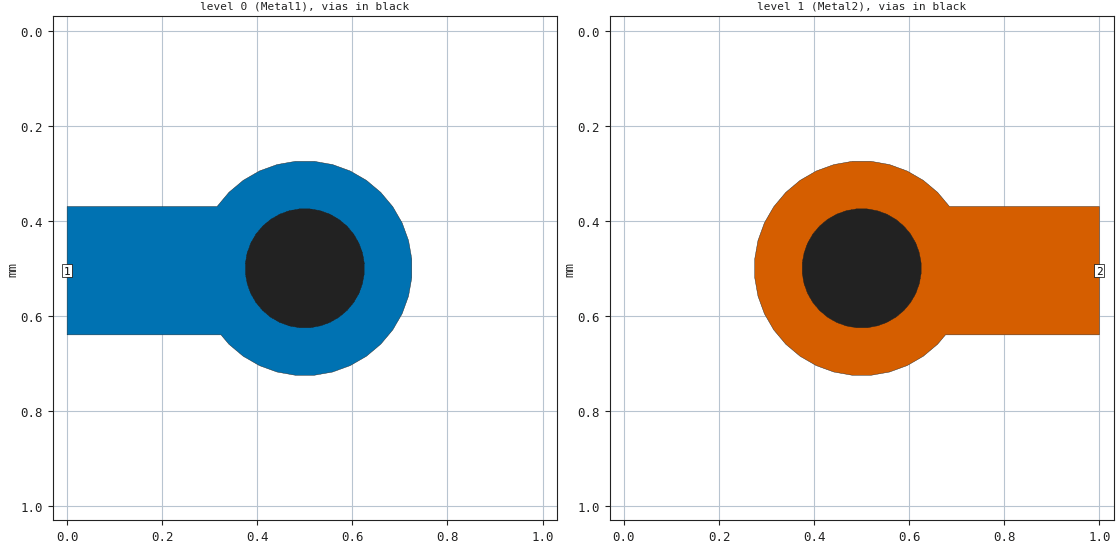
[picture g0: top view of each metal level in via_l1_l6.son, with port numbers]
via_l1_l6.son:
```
FTYP SONPROJ 17 ! Sonnet Project File
VER 17.52.2
HEADER
LIC antikernel2.1.48685 90e2ba8817c0 havequick azonenberg
DAT 07/11/2020 20:25:34
BUILT_BY_CREATED xgeom 16.56 07/03/2018 15:05:41
BUILT_BY_SAVED sonnet 17.52.2
MDATE 07/11/2020 20:25:34
HDATE 07/11/2020 20:25:34
END HEADER
DIM
ANG DEG
CAP PF
CON /OH
FREQ GHZ
IND NH
LNG MM
RES OH
END DIM
CONTROL
VARSWP
OPTIONS  -dj
SPEED 0
CACHE_ABS 1
Q_ACC N
END CONTROL
GEO
TMET "Free Space" 0 FREESPACE 376.7303136 0 0 0
BMET "Free Space" 0 FREESPACE 376.7303136 0 0 0
BRI "Alumina (96%)" 0 9.4 0.0004 0 
BRI "Alumina (99.5%)" 0 9.9 0.0001 0 
BRI "Aluminum Nitride" 0 8.6 0.0003 0 
BRI "Arlon 25FR" 0 3.58 0.0035 0 
BRI "Arlon 25N" 0 3.38 0.0025 0 
BRI "Arlon AD5" 0 5.1 0.003 0 
BRI "Arlon AD10" 0 10.2 0.005 0 
BRI "Arlon AD250" 0 2.5 0.0018 0 
BRI "Arlon AD255A" 0 2.55 0.0015 0 
BRI "Arlon AD260A" 0 2.6 0.0018 0 
BRI "Arlon AD270" 0 2.7 0.0023 0 
BRI "Arlon AD300A" 0 3 0.002 0 
BRI "Arlon AD320A" 0 3.2 0.0032 0 
BRI "Arlon AD350A" 0 3.5 0.003 0 
BRI "Arlon AD410" 0 4.1 0.003 0 
BRI "Arlon AD430" 0 4.3 0.003 0 
BRI "Arlon AD450" 0 4.5 0.0035 0 
BRI "Arlon AD600" 0 6.15 0.003 0 
BRI "Arlon AD1000" 0 10.2 0.0023 0 
BRI "Arlon AR1000" 0 9.8 0.003 0 
BRI "Arlon CLTE" 0 2.96 0.0023 0 
BRI "Arlon CLTE-AT" 0 3 0.0013 0 
BRI "Arlon CLTE-P" 0 2.94 0.0025 0 
BRI "Arlon CLTE-XT" 0 2.94 0.0012 0 
BRI "Arlon Cu 217LX" 0 2.17 0.0009 0 
BRI "Arlon Cu 233LX" 0 2.33 0.0013 0 
BRI "Arlon Cu 250GT" 0 2.5 0.001 0 
BRI "Arlon Cu 250GX" 0 2.5 0.0018 0 
BRI "Arlon Cu 6250" 0 2.32 0.0013 0 
BRI "Arlon Cu 6700" 0 2.35 0.0025 0 
BRI "Arlon Di 522" 0 2.5 0.001 0 
BRI "Arlon Di 527" 0 2.5 0.0018 0 
BRI "Arlon Di 870" 0 2.33 0.0013 0 
BRI "Arlon Di 880" 0 2.17 0.0009 0 
BRI "Arlon Iso 917" 0 2.17 0.0013 0 
BRI "Arlon Iso 933" 0 2.33 0.0016 0 
BRI "Arlon Multi HF" 0 3.7 0.004 0 
BRI "Arlon TC350" 0 3.5 0.002 0 
BRI "Arlon TC600" 0 6.15 0.002 0 
BRI "Beryllia (99.5%)" 0 6.5 0.0004 0 
BRI "CEM-1" 0 4.5 0.02 0 
BRI "CEM-3" 0 4.5 0.02 0 
BRI "Dupont 9K7" 0 7.1 0.0012 0 
BRI "Dupont 943" 0 7.4 0.002 0 
BRI "Dupont 951" 0 7.8 0.006 0 
BRI "Dupont FEP" 0 2 0.0005 0 
BRI "Dupont Vacrel" 0 3.8 0.011 0 
BRI "ESL 41010" 0 7.5 0.005 0 
BRI "ESL 41020" 0 7.25 0.005 0 
BRI "ESL 41050" 0 13.5 0.002 0 
BRI "ESL 41060" 0 16.5 0.002 0 
BRI "ESL 41110" 0 4.5 0.004 0 
BRI "Ferro A6M" 0 5.9 0.002 0 
BRI "Ferro A6S" 0 5.9 0.002 0 
BRI "Ferro L8" 0 7.3 0.0018 0 
BRI "FR-4" 0 4.4 0.02 0 
BRI "G-10" 0 4.8 0.025 0 
BRI "Gallium Arsenide" 0 12.9 0.006 0 
BRI "Gallium Nitride" 0 9.7 0 0 
BRI "Glass (Pyrex)" 0 4.82 0.0054 0 
BRI "Heraeus HL2000" 0 7.3 0.0026 0 
BRI "Isola 370HR" 0 4.04 0.021 0 
BRI "Isola FR408" 0 3.77 0.0116 0 
BRI "Isola FR408HR" 0 3.68 0.0092 0 
BRI "Isola Getek" 0 3.6 0.01 0 
BRI "Isola GI-180" 0 3.7 0.013 0 
BRI "Isola IS415" 0 3.82 0.0125 0 
BRI "Isola IS620i" 0 3.58 0.006 0 
BRI "Isola IS680-280" 0 2.8 0.0025 0 
BRI "Isola IS680-300" 0 3 0.003 0 
BRI "Isola IS680-320" 0 3.2 0.003 0 
BRI "Isola IS680-333" 0 3.33 0.003 0 
BRI "Isola IS680-338" 0 3.38 0.0032 0 
BRI "Isola IS680-345" 0 3.45 0.0036 0 
BRI "Kerafol CT800" 0 5.3 0.008 0 
BRI "Nelco MW9350" 0 3.7 0.004 0 
BRI "Nelco N4000-12" 0 3.7 0.008 0 
BRI "Nelco N4000-13" 0 3.7 0.009 0 
BRI "Nelco N4000-13SI" 0 3.2 0.007 0 
BRI "Nelco N4000-13EP" 0 3.7 0.008 0 
BRI "Nelco N4350-13RF" 0 3.5 0.0065 0 
BRI "Nelco N4380-13RF" 0 3.8 0.007 0 
BRI "Nelco N9300-13RF" 0 3 0.004 0 
BRI "Nelco N9320-13RF" 0 3.2 0.0045 0 
BRI "Nelco N9338-13RF" 0 3.38 0.0046 0 
BRI "Nelco N9350-13RF" 0 3.48 0.0055 0 
BRI "Nelco NH9294" 0 2.94 0.0022 0 
BRI "Nelco NH9300" 0 3 0.0023 0 
BRI "Nelco NH9320" 0 3.2 0.0024 0 
BRI "Nelco NH9338" 0 3.38 0.0025 0 
BRI "Nelco NH9348" 0 3.48 0.003 0 
BRI "Nelco NH9350" 0 3.5 0.003 0 
BRI "Nelco NH9410" 0 4.1 0.003 0 
BRI "Nelco NH9450" 0 4.5 0.003 0 
BRI "Nelco NX9240" 0 2.4 0.0016 0 
BRI "Nelco NX9245" 0 2.45 0.0016 0 
BRI "Nelco NX9250" 0 2.5 0.0017 0 
BRI "Nelco NX9255" 0 2.55 0.0018 0 
BRI "Nelco NX9260" 0 2.6 0.0019 0 
BRI "Nelco NY9208" 0 2.08 0.0006 0 
BRI "Nelco NY9217" 0 2.17 0.0008 0 
BRI "Nelco NY9220" 0 2.2 0.0009 0 
BRI "Nelco NY9233" 0 2.33 0.0011 0 
BRI "PET" 0 3.37 0.0208 0 
BRI "Polyimide" 0 3.5 0.003 0 
BRI "Quartz (Fused)" 0 3.78 0.0001 0 
BRI "Rogers 3001" 0 2.28 0.003 0 
BRI "Rogers RO2808" 0 7.6 0.0015 0 
BRI "Rogers RO3003" 0 3 0.0013 0 
BRI "Rogers RO3006" 0 6.5 0.002 0 
BRI "Rogers RO3010" 0 11.2 0.0022 0 
BRI "Rogers RO3035" 0 3.6 0.0018 0 
BRI "Rogers RO3203" 0 3.02 0.0016 0 
BRI "Rogers RO3206" 0 6.6 0.0027 0 
BRI "Rogers RO3210" 0 10.8 0.0027 0 
BRI "Rogers RO3730" 0 3 0.0016 0 
BRI "Rogers RO4003C" 0 3.55 0.0029 0 
BRI "Rogers RO4533" 0 3.45 0.0029 0 
BRI "Rogers RO4534" 0 3.4 0.003 0 
BRI "Rogers RO4350B" 0 3.66 0.0037 0 
BRI "Rogers RO4350BTX" 0 3.66 0.0034 0 
BRI "Rogers RO4360" 0 6.15 0.0038 0 
BRI "Rogers RO4450B-3.6" 0 3.3 0.0043 0 
BRI "Rogers RO4450B-4" 0 3.54 0.004 0 
BRI "Rogers RO4450F" 0 3.52 0.0041 0 
BRI "Rogers RO4730" 0 3 0.0033 0 
BRI "Rogers RT5870" 0 2.33 0.0012 0 
BRI "Rogers RT5880" 0 2.2 0.0009 0 
BRI "Rogers RT5880LZ" 0 1.96 0.0019 0 
BRI "Rogers RT6002" 0 2.94 0.0012 0 
BRI "Rogers RT6006" 0 6.15 0.0027 0 
BRI "Rogers RT6010LM" 0 10.9 0.0023 0 
BRI "Rogers RT6035HTC" 0 3.6 0.0013 0 
BRI "Rogers RT6202" 0 2.94 0.0015 0 
BRI "Rogers RT6202PR" 0 2.95 0.0015 0 
BRI "Rogers Syron7000" 0 3.4 0.0045 0 
BRI "Rogers Syron7100-2" 0 3.61 0.006 0 
BRI "Rogers Syron7100-4" 0 3.39 0.005 0 
BRI "Rogers Theta" 0 4.01 0.0118 0 
BRI "Rogers TMM 3" 0 3.39 0.002 0 
BRI "Rogers TMM 4" 0 4.5 0.002 0 
BRI "Rogers TMM 6" 0 6 0.0023 0 
BRI "Rogers TMM 10" 0 9.56 0.0022 0 
BRI "Rogers TMM 10i" 0 9.96 0.002 0 
BRI "Rogers UL2000" 0 2.5 0.0019 0 
BRI "Rogers UL3850" 0 3.05 0.0025 0 
BRI "Rogers UL3908" 0 2.9 0.0025 0 
BRI "Rogers XT8000" 0 3.34 0.0035 0 
BRI "Rogers XT8100-2" 0 3.54 0.0049 0 
BRI "Rogers XT8100-4" 0 3.32 0.0038 0 
BRI "Silicon (intrinsic)" 0 11.9 0.004 0.00044 
BRI "Silicon Dioxide" 0 3.9 0 0 
BRI "Silicon Nitride" 0 7.5 0 0 
BRI "Taconic CER-10" 0 10 0.0035 0 
BRI "Taconic FastFilm" 0 2.7 0.0012 0 
BRI "Taconic Fastrise-DS" 0 2.96 0.0018 0 
BRI "Taconic Fastrise27" 0 2.7 0.0014 0 
BRI "Taconic Fastrise77" 0 7.7 0.0034 0 
BRI "Taconic FEP" 0 2 0.0003 0 
BRI "Taconic RF-30" 0 3 0.0014 0 
BRI "Taconic RF-35" 0 3.5 0.0018 0 
BRI "Taconic RF-35A2" 0 3.5 0.0011 0 
BRI "Taconic RF-35P" 0 3.5 0.0025 0 
BRI "Taconic RF-41" 0 4.1 0.0038 0 
BRI "Taconic RF-43" 0 4.3 0.0033 0 
BRI "Taconic RF-45" 0 4.5 0.0037 0 
BRI "Taconic RF-60A" 0 6.15 0.0038 0 
BRI "Taconic RF-301" 0 2.97 0.0012 0 
BRI "Taconic TacBond HT" 0 2.35 0.0025 0 
BRI "Taconic TLA-6" 0 2.62 0.0012 0 
BRI "Taconic TLC-27" 0 2.75 0.003 0 
BRI "Taconic TLC-30" 0 3 0.003 0 
BRI "Taconic TLC-32" 0 3.2 0.003 0 
BRI "Taconic TLE-95" 0 2.95 0.0028 0 
BRI "Taconic TLF-34" 0 3.4 0.002 0 
BRI "Taconic TLF-35" 0 3.5 0.002 0 
BRI "Taconic TLP-3" 0 2.33 0.0009 0 
BRI "Taconic TLP-5" 0 2.2 0.0009 0 
BRI "Taconic TLP-5A" 0 2.17 0.0009 0 
BRI "Taconic TLT-0" 0 2.45 0.0006 0 
BRI "Taconic TLT-9" 0 2.5 0.0006 0 
BRI "Taconic TLT-8" 0 2.55 0.0006 0 
BRI "Taconic TLT-7" 0 2.6 0.0006 0 
BRI "Taconic TLT-6" 0 2.65 0.0006 0 
BRI "Taconic TLX-0" 0 2.45 0.0019 0 
BRI "Taconic TLX-9" 0 2.5 0.0019 0 
BRI "Taconic TLX-8" 0 2.55 0.0019 0 
BRI "Taconic TLX-7" 0 2.6 0.0019 0 
BRI "Taconic TLX-6" 0 2.65 0.0019 0 
BRI "Taconic TLY-3" 0 2.33 0.0009 0 
BRI "Taconic TLY-3F" 0 2.33 0.0009 0 
BRI "Taconic TLY-5" 0 2.2 0.0009 0 
BRI "Taconic TLY-5-L" 0 2.2 0.0009 0 
BRI "Taconic TLY-5A" 0 2.17 0.0009 0 
BRI "Taconic TLY-5A-L" 0 2.17 0.0009 0 
BRI "Taconic TPG-30" 0 3 0.0038 0 
BRI "Taconic TPG-32" 0 3.2 0.005 0 
BRI "Taconic TPG-35" 0 3.5 0.005 0 
BRI "Taconic TRF-41" 0 4.1 0.0035 0 
BRI "Taconic TRF-43" 0 4.3 0.0035 0 
BRI "Taconic TRF-45" 0 4.5 0.0035 0 
BRI "Taconic TSM-DS" 0 2.85 0.001 0 
BRI "Taconic TSM-DS3" 0 3 0.0011 0 
BRI "Taconic TSM-26" 0 2.6 0.0014 0 
BRI "Taconic TSM-29" 0 2.94 0.0013 0 
BRI "Taconic TSM-30" 0 3 0.0013 0 
BRI "Teflon (PTFE)" 0 2.08 0.0004 0 
BOX 2 1 1 200 200 20 0
      2 1 1 0 0 0 0 "Air"
      1.22 3.66 1 0.0037 0 0 0 "Rogers RO4350B"
      2 1 1 0 0 0 0 "Air"
TECHLAY METAL Metal1 <UNSPECIFIED> -2 0 
0 0 -1 N 0 1 1 100 100 0 0 0 Y
END
END
TECHLAY METAL Metal2 <UNSPECIFIED> -3 0 
1 0 -1 N 0 1 1 100 100 0 0 0 Y
END
END
TECHLAY VIA Via1 <UNSPECIFIED> -4 0 
VIA POLYGON
1 0 -1 N 0 1 1 100 100 0 0 0 Y
TOLEVEL 0 RING NOCOVERS
END
END
LORGN 0 250 U 
POR1 BOX
POLY 2167 1
24
1 50 0 0 0 0 0.505 
POR1 BOX
POLY 2174 1
5
2 50 0 0 0 1 0.505 
NUM 3
0 34 -1 N 2167 1 1 100 100 0 0 0 Y
TLAYNAM Metal1 INH
0.5584567307 0.7181634889
0.5954523338 0.7046981905
0.6295476662 0.6850132412
0.6597067582 0.6597067582
0.6850132412 0.6295476662
0.7046981905 0.5954523338
0.7181634889 0.5584567307
0.725 0.5196849493
0.725 0.5196849493
0.725 0.4803150507
0.7181634889 0.4415432693
0.7046981905 0.4045476662
0.6850132412 0.3704523338
0.6597067582 0.3402932418
0.6295476662 0.3149867588
0.5954523338 0.2953018095
0.5584567307 0.2818365111
0.5196849493 0.275
0.4803150507 0.275
0.4415432693 0.2818365111
0.4045476662 0.2953018095
0.3704523338 0.3149867588
0.3402932418 0.3402932418
0.315366312 0.37
0 0.37
0 0.64
0.3237573083 0.64
0.3402932418 0.6597067582
0.3704523338 0.6850132412
0.4045476662 0.7046981905
0.4415432693 0.7181634889
0.4803150507 0.725
0.5196849493 0.725
0.5584567307 0.7181634889
END
VIA POLYGON
0 37 -1 N 2170 1 1 100 100 0 0 0 Y
TOLEVEL 1 RING NOCOVERS
0.625 0.5109360829
0.6212019383 0.5324759615
0.6137212169 0.5530290744
0.602785134 0.5719709256
0.5887259768 0.5887259768
0.5719709256 0.602785134
0.5530290744 0.6137212169
0.5324759615 0.6212019383
0.5109360829 0.625
0.4890639171 0.625
0.4675240385 0.6212019383
0.4469709256 0.6137212169
0.4280290744 0.602785134
0.4112740232 0.5887259768
0.397214866 0.5719709256
0.3862787831 0.5530290744
0.3787980617 0.5324759615
0.375 0.5109360829
0.375 0.4890639171
0.3787980617 0.4675240385
0.3862787831 0.4469709256
0.397214866 0.4280290744
0.4112740232 0.4112740232
0.4280290744 0.397214866
0.4469709256 0.3862787831
0.4675240385 0.3787980617
0.4890639171 0.375
0.5109360829 0.375
0.5324759615 0.3787980617
0.5530290744 0.3862787831
0.5719709256 0.397214866
0.5887259768 0.4112740232
0.602785134 0.4280290744
0.6137212169 0.4469709256
0.6212019383 0.4675240385
0.625 0.4890639171
0.625 0.5109360829
END
1 33 -1 N 2174 1 1 100 100 0 0 0 Y
TLAYNAM Metal2 INH
0.5584567307 0.7181634889
0.5954523338 0.7046981905
0.6295476662 0.6850132412
0.6597067582 0.6597067582
0.6762426917 0.64
1 0.64
1 0.37
0.684633688 0.37
0.6597067582 0.3402932418
0.6295476662 0.3149867588
0.5954523338 0.2953018095
0.5584567307 0.2818365111
0.5196849493 0.275
0.4803150507 0.275
0.4415432693 0.2818365111
0.4045476662 0.2953018095
0.3704523338 0.3149867588
0.3402932418 0.3402932418
0.3149867588 0.3704523338
0.2953018095 0.4045476662
0.2818365111 0.4415432693
0.275 0.4803150507
0.275 0.5196849493
0.2818365111 0.5584567307
0.2953018095 0.5954523338
0.3149867588 0.6295476662
0.3402932418 0.6597067582
0.3704523338 0.6850132412
0.4045476662 0.7046981905
0.4415432693 0.7181634889
0.4803150507 0.725
0.5196849493 0.725
0.5584567307 0.7181634889
END
END GEO
OPT
MAX 100
END OPT
VARSWP
ENABLED Y
FREQ Y AY ABS_ENTRY 0.01 10.0 -1 300 
END
END VARSWP
```
